VERSION 5.8 ;
BUSBITCHARS "[]" ;
DIVIDERCHAR "/" ;
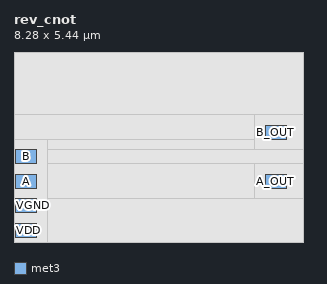
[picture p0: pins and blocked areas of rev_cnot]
MACRO rev_cnot
  CLASS BLOCK ;
  ORIGIN 0 0 ;
  FOREIGN rev_cnot 0 0 ;
  SIZE 8.280 BY 5.440 ;
  SYMMETRY X Y ;
  PIN VDD
    DIRECTION INOUT ;
    USE POWER ;
    PORT
      LAYER met3 ;
      RECT 0.050 0.140 0.650 0.540 ;
    END
  END VDD
  PIN VGND
    DIRECTION INOUT ;
    USE GROUND ;
    PORT
      LAYER met3 ;
      RECT 0.050 0.840 0.650 1.240 ;
    END
  END VGND
  PIN A
    DIRECTION INPUT ;
    USE SIGNAL ;
    PORT
      LAYER met3 ;
      RECT 0.050 1.540 0.650 1.940 ;
    END
  END A
  PIN B
    DIRECTION INPUT ;
    USE SIGNAL ;
    PORT
      LAYER met3 ;
      RECT 0.050 2.240 0.650 2.640 ;
    END
  END B
  PIN A_OUT
    DIRECTION OUTPUT ;
    USE SIGNAL ;
    PORT
      LAYER met3 ;
      RECT 7.190 1.540 7.790 1.940 ;
    END
  END A_OUT
  PIN B_OUT
    DIRECTION OUTPUT ;
    USE SIGNAL ;
    PORT
      LAYER met3 ;
      RECT 7.190 2.940 7.790 3.340 ;
    END
  END B_OUT
  OBS
    LAYER li1 ;
    RECT 0.000 0.000 8.280 5.440 ;
    LAYER met1 ;
    RECT 0.000 0.000 8.280 5.440 ;
    LAYER met2 ;
    RECT 0.000 0.000 8.280 5.440 ;
    LAYER met3 ;
    RECT 0.950 0.000 8.280 1.240 ;
    RECT 0.950 1.240 6.890 2.240 ;
    RECT 0.950 2.240 8.280 2.640 ;
    RECT 0.950 2.640 6.890 2.940 ;
    RECT 0.000 2.940 6.890 3.640 ;
    RECT 0.000 3.640 8.280 5.440 ;
  END
END rev_cnot
END LIBRARY
